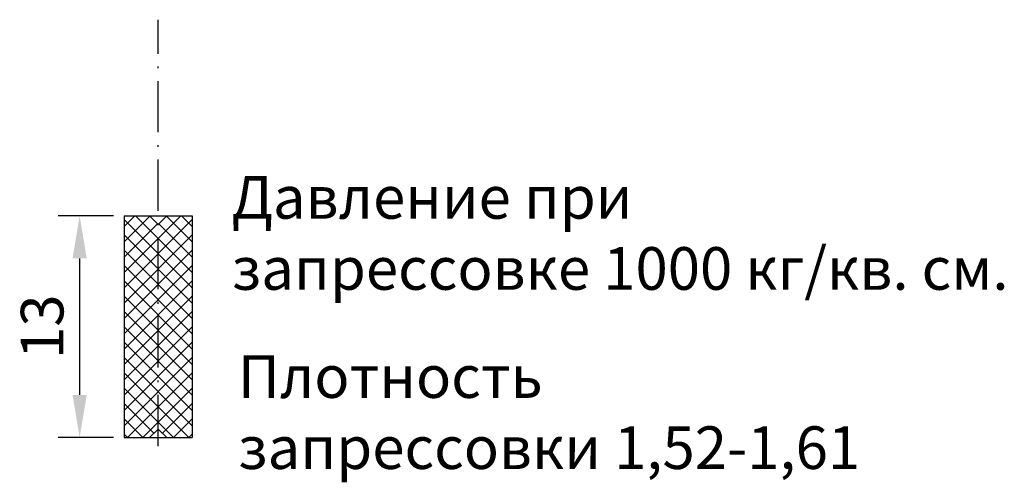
# Model space of a CAD drawing. Units: millimetres. Extents: x -8.1 to 49.6, y -2.6 to 24.5.
import ezdxf

# ---------------------------------------------------------------- set-up
doc = ezdxf.new("R2010")
doc.units = ezdxf.units.MM
doc.linetypes.add('ACAD_ISO10W100', pattern=[18, 12, -3, 0, -3])
doc.dimstyles.new('ISO-25', dxfattribs={"dimtxt": 2.5, "dimasz": 2.5, "dimexe": 1.25, "dimexo": 0.625, "dimtad": 1, "dimtxsty": 'Standard', "dimcen": 2.5, "dimadec": 0, "dimazin": 0, "dimtfac": 1, "dimtmove": 0, "dimatfit": 3, "dimfxl": 0, "dimarcsym": 0})

# ---------------------------------------------------------------- blocks, each defined once
blk = doc.blocks.new('*D5')
at = {"color": 0, "lineweight": -2, "ltscale": 0.25}
for p, q in [((-2.625, 13), (-5.857, 13)), ((-4.607, 10.5), (-4.607, 2.5)), ((-2.625, 0), (-5.857, 0))]:
    blk.add_line(p, q, dxfattribs=at)
at = {"color": 0, "lineweight": 15, "ltscale": 0.25}
for points in [[(-5.024, 10.5), (-4.19, 10.5), (-4.607, 13)], [(-5.024, 2.5), (-4.19, 2.5), (-4.607, 0)]]:
    blk.add_solid(points, dxfattribs=at)
at = {"layer": 'Defpoints', "color": 0, "lineweight": 15, "ltscale": 0.25}
for p in [(-2, 13), (-4.607, 0), (-2, 0)]:
    blk.add_point(p, dxfattribs=at)
at = {"color": 0, "lineweight": 15, "ltscale": 0.25, "insert": (-6.482, 6.5), "char_height": 2.5, "attachment_point": 5, "rotation": 90}
blk.add_mtext('13', dxfattribs=at)

msp = doc.modelspace()

# ---------------------------------------------------------------- hatches: boundary and pattern name
at = {"lineweight": 15, "ltscale": 0.25}
h = msp.add_hatch(dxfattribs=at)
h.set_pattern_fill('ANSI37', scale=0.2, angle=90, style=0)
h.paths.add_polyline_path([(0, 12.5), (-0.5, 13), (-2, 13), (-2, 0), (-0.5, 0), (0, 0.5)])
h.paths.add_polyline_path([(2, 13), (0.5, 13), (0, 12.5), (0, 0.5), (0.5, 0), (2, 0)])

# ---------------------------------------------------------------- linework, layer by layer
at = {"color": 1, "linetype": 'ACAD_ISO10W100', "lineweight": 25, "ltscale": 0.25}
msp.add_line((0, -0.5), (0, 24.5), dxfattribs=at)
at = {"color": 7, "lineweight": 30, "ltscale": 0.25}
for p, q in [((-2, 13), (-2, 0)), ((-2, 13), (2, 13)), ((-0.5, 13), (0, 12.5)), ((0, 12.5), (0.5, 13)), ((2, 13), (2, 0)), ((-2, 0), (2, 0)), ((0, 0.5), (-0.5, 0)), ((0.5, 0), (0, 0.5))]:
    msp.add_line(p, q, dxfattribs=at)

# ---------------------------------------------------------------- texts
at = {"color": 7, "lineweight": 15, "ltscale": 0.25}
for s, p in [('Давление при', (4.301, 12.832)), ('запрессовке 1000 кг/кв. см.', (4.301, 8.665)), ('Плотность', (4.675, 2.326)), ('запрессовки 1,52-1,61', (4.675, -1.841))]:
    msp.add_text(s, height=2.5, dxfattribs=at).set_placement(p)

# ---------------------------------------------------------------- dimensions: what is measured, and where the dimension line sits
dim = msp.add_linear_dim(base=(-4.607, 0), p1=(-2, 13), p2=(-2, 0), angle=90, dimstyle='ISO-25', dxfattribs=at)
dim.commit()
dim.dimension.update_dxf_attribs({"geometry": '*D5', "text_midpoint": (-6.482, 6.5)})

doc.saveas('drawing.dxf')
